VERSION 5.7 ;
  NOWIREEXTENSIONATPIN ON ;
  DIVIDERCHAR "/" ;
  BUSBITCHARS "[]" ;
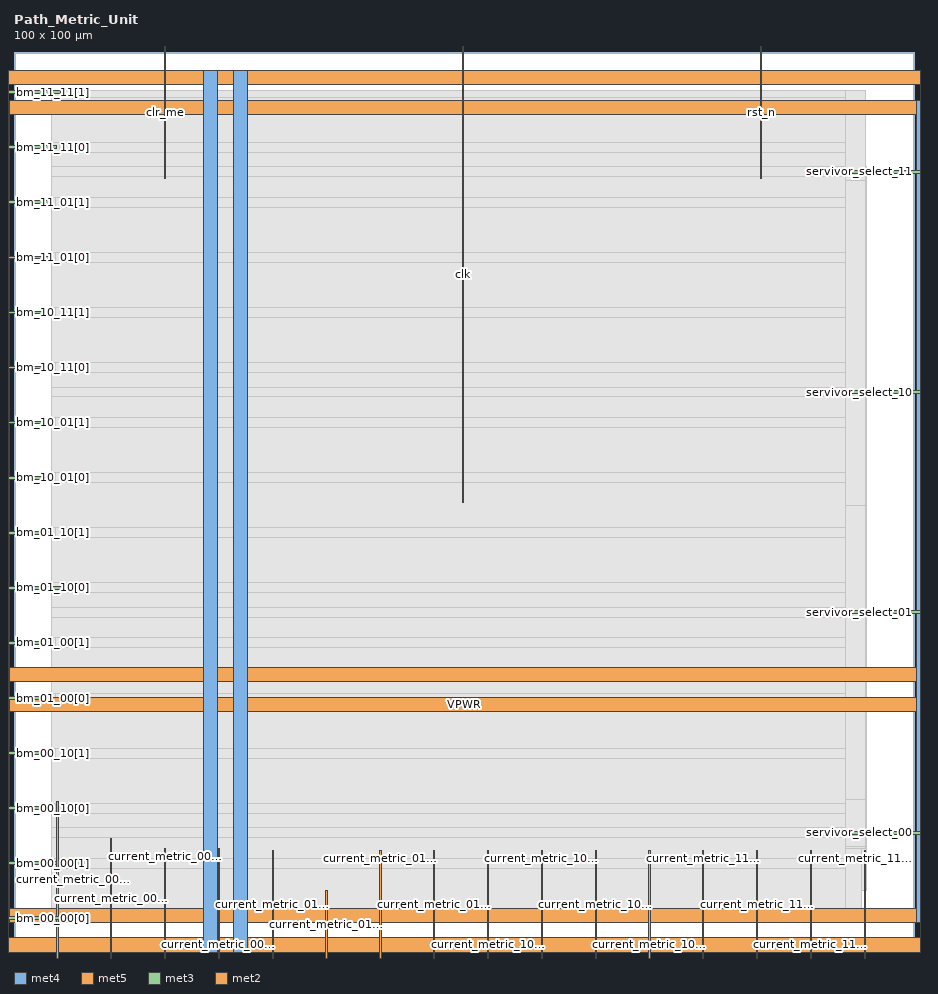
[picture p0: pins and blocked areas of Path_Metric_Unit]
MACRO Path_Metric_Unit
  CLASS BLOCK ;
  FOREIGN Path_Metric_Unit ;
  ORIGIN 0.000 0.000 ;
  SIZE 100.000 BY 100.000 ;
  PIN VGND
    DIRECTION INOUT ;
    USE GROUND ;
    PORT
      LAYER met4 ;
        RECT -5.380 -0.020 -3.780 97.940 ;
    END
    PORT
      LAYER met5 ;
        RECT -5.380 -0.020 105.200 1.580 ;
    END
    PORT
      LAYER met5 ;
        RECT -5.380 96.340 105.200 97.940 ;
    END
    PORT
      LAYER met4 ;
        RECT 103.600 -0.020 105.200 97.940 ;
    END
    PORT
      LAYER met4 ;
        RECT 24.340 -0.020 25.940 97.940 ;
    END
    PORT
      LAYER met5 ;
        RECT -5.380 30.030 105.200 31.630 ;
    END
  END VGND
  PIN VPWR
    DIRECTION INOUT ;
    USE POWER ;
    PORT
      LAYER met4 ;
        RECT -2.080 3.280 -0.480 94.640 ;
    END
    PORT
      LAYER met5 ;
        RECT -2.080 3.280 101.900 4.880 ;
    END
    PORT
      LAYER met5 ;
        RECT -2.080 93.040 101.900 94.640 ;
    END
    PORT
      LAYER met4 ;
        RECT 100.300 3.280 101.900 94.640 ;
    END
    PORT
      LAYER met4 ;
        RECT 21.040 -0.020 22.640 97.940 ;
    END
    PORT
      LAYER met5 ;
        RECT -5.380 26.730 105.200 28.330 ;
    END
  END VPWR
  PIN bm_00_00[0]
    DIRECTION INPUT ;
    USE SIGNAL ;
    ANTENNAGATEAREA 0.196500 ;
    PORT
      LAYER met3 ;
        RECT -1.000 3.590 6.530 3.890 ;
    END
  END bm_00_00[0]
  PIN bm_00_00[1]
    DIRECTION INPUT ;
    USE SIGNAL ;
    ANTENNAGATEAREA 0.196500 ;
    PORT
      LAYER met3 ;
        RECT -1.000 9.710 7.450 10.010 ;
    END
  END bm_00_00[1]
  PIN bm_00_10[0]
    DIRECTION INPUT ;
    USE SIGNAL ;
    ANTENNAGATEAREA 0.196500 ;
    PORT
      LAYER met3 ;
        RECT -1.000 15.830 4.230 16.130 ;
    END
  END bm_00_10[0]
  PIN bm_00_10[1]
    DIRECTION INPUT ;
    USE SIGNAL ;
    ANTENNAGATEAREA 0.196500 ;
    PORT
      LAYER met3 ;
        RECT -1.000 21.950 4.230 22.250 ;
    END
  END bm_00_10[1]
  PIN bm_01_00[0]
    DIRECTION INPUT ;
    USE SIGNAL ;
    ANTENNAGATEAREA 0.196500 ;
    PORT
      LAYER met3 ;
        RECT -1.000 28.070 4.230 28.370 ;
    END
  END bm_01_00[0]
  PIN bm_01_00[1]
    DIRECTION INPUT ;
    USE SIGNAL ;
    ANTENNAGATEAREA 0.196500 ;
    PORT
      LAYER met3 ;
        RECT -1.000 34.190 4.230 34.490 ;
    END
  END bm_01_00[1]
  PIN bm_01_10[0]
    DIRECTION INPUT ;
    USE SIGNAL ;
    ANTENNAGATEAREA 0.196500 ;
    PORT
      LAYER met3 ;
        RECT -1.000 40.310 6.990 40.610 ;
    END
  END bm_01_10[0]
  PIN bm_01_10[1]
    DIRECTION INPUT ;
    USE SIGNAL ;
    ANTENNAGATEAREA 0.196500 ;
    PORT
      LAYER met3 ;
        RECT -1.000 46.430 4.230 46.730 ;
    END
  END bm_01_10[1]
  PIN bm_10_01[0]
    DIRECTION INPUT ;
    USE SIGNAL ;
    ANTENNAGATEAREA 0.196500 ;
    PORT
      LAYER met3 ;
        RECT -1.000 52.550 4.230 52.850 ;
    END
  END bm_10_01[0]
  PIN bm_10_01[1]
    DIRECTION INPUT ;
    USE SIGNAL ;
    ANTENNAGATEAREA 0.196500 ;
    PORT
      LAYER met3 ;
        RECT -1.000 58.670 4.230 58.970 ;
    END
  END bm_10_01[1]
  PIN bm_10_11[0]
    DIRECTION INPUT ;
    USE SIGNAL ;
    ANTENNAGATEAREA 0.196500 ;
    PORT
      LAYER met3 ;
        RECT -1.000 64.790 4.230 65.090 ;
    END
  END bm_10_11[0]
  PIN bm_10_11[1]
    DIRECTION INPUT ;
    USE SIGNAL ;
    ANTENNAGATEAREA 0.196500 ;
    PORT
      LAYER met3 ;
        RECT -1.000 70.910 4.230 71.210 ;
    END
  END bm_10_11[1]
  PIN bm_11_01[0]
    DIRECTION INPUT ;
    USE SIGNAL ;
    ANTENNAGATEAREA 0.196500 ;
    PORT
      LAYER met3 ;
        RECT -1.000 77.030 4.230 77.330 ;
    END
  END bm_11_01[0]
  PIN bm_11_01[1]
    DIRECTION INPUT ;
    USE SIGNAL ;
    ANTENNAGATEAREA 0.196500 ;
    PORT
      LAYER met3 ;
        RECT -1.000 83.150 4.230 83.450 ;
    END
  END bm_11_01[1]
  PIN bm_11_11[0]
    DIRECTION INPUT ;
    USE SIGNAL ;
    ANTENNAGATEAREA 0.196500 ;
    PORT
      LAYER met3 ;
        RECT -1.000 89.270 4.690 89.570 ;
    END
  END bm_11_11[0]
  PIN bm_11_11[1]
    DIRECTION INPUT ;
    USE SIGNAL ;
    ANTENNAGATEAREA 0.196500 ;
    PORT
      LAYER met3 ;
        RECT -1.000 95.390 5.150 95.690 ;
    END
  END bm_11_11[1]
  PIN clk
    DIRECTION INPUT ;
    USE SIGNAL ;
    ANTENNAGATEAREA 0.852000 ;
    PORT
      LAYER met2 ;
        RECT 49.840 49.940 49.980 101.000 ;
    END
  END clk
  PIN clr_me
    DIRECTION INPUT ;
    USE SIGNAL ;
    ANTENNAGATEAREA 0.196500 ;
    PORT
      LAYER met2 ;
        RECT 16.720 85.980 16.860 101.000 ;
    END
  END clr_me
  PIN current_metric_00[0]
    DIRECTION OUTPUT ;
    USE SIGNAL ;
    ANTENNADIFFAREA 0.445500 ;
    PORT
      LAYER met2 ;
        RECT 4.760 -1.000 4.900 16.700 ;
    END
  END current_metric_00[0]
  PIN current_metric_00[1]
    DIRECTION OUTPUT ;
    USE SIGNAL ;
    ANTENNADIFFAREA 0.445500 ;
    PORT
      LAYER met2 ;
        RECT 10.740 -1.000 10.880 12.620 ;
    END
  END current_metric_00[1]
  PIN current_metric_00[2]
    DIRECTION OUTPUT ;
    USE SIGNAL ;
    ANTENNADIFFAREA 0.445500 ;
    PORT
      LAYER met2 ;
        RECT 16.720 -1.000 16.860 11.460 ;
    END
  END current_metric_00[2]
  PIN current_metric_00[3]
    DIRECTION OUTPUT ;
    USE SIGNAL ;
    ANTENNADIFFAREA 0.445500 ;
    PORT
      LAYER met2 ;
        RECT 22.700 -1.000 22.840 11.460 ;
    END
  END current_metric_00[3]
  PIN current_metric_01[0]
    DIRECTION OUTPUT ;
    USE SIGNAL ;
    ANTENNADIFFAREA 0.445500 ;
    PORT
      LAYER met2 ;
        RECT 28.680 -1.000 28.820 11.260 ;
    END
  END current_metric_01[0]
  PIN current_metric_01[1]
    DIRECTION OUTPUT ;
    USE SIGNAL ;
    ANTENNADIFFAREA 0.445500 ;
    PORT
      LAYER met2 ;
        RECT 34.660 -1.000 34.800 6.840 ;
    END
  END current_metric_01[1]
  PIN current_metric_01[2]
    DIRECTION OUTPUT ;
    USE SIGNAL ;
    ANTENNADIFFAREA 0.445500 ;
    PORT
      LAYER met2 ;
        RECT 40.640 -1.000 40.780 11.260 ;
    END
  END current_metric_01[2]
  PIN current_metric_01[3]
    DIRECTION OUTPUT ;
    USE SIGNAL ;
    ANTENNADIFFAREA 0.445500 ;
    PORT
      LAYER met2 ;
        RECT 46.620 -1.000 46.760 11.260 ;
    END
  END current_metric_01[3]
  PIN current_metric_10[0]
    DIRECTION OUTPUT ;
    USE SIGNAL ;
    ANTENNADIFFAREA 0.445500 ;
    PORT
      LAYER met2 ;
        RECT 52.600 -1.000 52.740 11.260 ;
    END
  END current_metric_10[0]
  PIN current_metric_10[1]
    DIRECTION OUTPUT ;
    USE SIGNAL ;
    ANTENNADIFFAREA 0.445500 ;
    PORT
      LAYER met2 ;
        RECT 58.580 -1.000 58.720 11.260 ;
    END
  END current_metric_10[1]
  PIN current_metric_10[2]
    DIRECTION OUTPUT ;
    USE SIGNAL ;
    ANTENNADIFFAREA 0.445500 ;
    PORT
      LAYER met2 ;
        RECT 64.560 -1.000 64.700 11.260 ;
    END
  END current_metric_10[2]
  PIN current_metric_10[3]
    DIRECTION OUTPUT ;
    USE SIGNAL ;
    ANTENNADIFFAREA 0.445500 ;
    PORT
      LAYER met2 ;
        RECT 70.540 -1.000 70.680 11.260 ;
    END
  END current_metric_10[3]
  PIN current_metric_11[0]
    DIRECTION OUTPUT ;
    USE SIGNAL ;
    ANTENNADIFFAREA 0.445500 ;
    PORT
      LAYER met2 ;
        RECT 76.520 -1.000 76.660 11.260 ;
    END
  END current_metric_11[0]
  PIN current_metric_11[1]
    DIRECTION OUTPUT ;
    USE SIGNAL ;
    ANTENNADIFFAREA 0.445500 ;
    PORT
      LAYER met2 ;
        RECT 82.500 -1.000 82.640 11.260 ;
    END
  END current_metric_11[1]
  PIN current_metric_11[2]
    DIRECTION OUTPUT ;
    USE SIGNAL ;
    ANTENNADIFFAREA 0.445500 ;
    PORT
      LAYER met2 ;
        RECT 88.480 -1.000 88.620 11.260 ;
    END
  END current_metric_11[2]
  PIN current_metric_11[3]
    DIRECTION OUTPUT ;
    USE SIGNAL ;
    ANTENNADIFFAREA 0.445500 ;
    PORT
      LAYER met2 ;
        RECT 94.460 -1.000 94.600 11.260 ;
    END
  END current_metric_11[3]
  PIN rst_n
    DIRECTION INPUT ;
    USE SIGNAL ;
    ANTENNAGATEAREA 0.196500 ;
    PORT
      LAYER met2 ;
        RECT 82.960 85.980 83.100 101.000 ;
    END
  END rst_n
  PIN servivor_select_00
    DIRECTION OUTPUT ;
    USE SIGNAL ;
    ANTENNADIFFAREA 0.445500 ;
    PORT
      LAYER met3 ;
        RECT 92.370 13.110 101.000 13.410 ;
    END
  END servivor_select_00
  PIN servivor_select_01
    DIRECTION OUTPUT ;
    USE SIGNAL ;
    ANTENNADIFFAREA 0.445500 ;
    PORT
      LAYER met3 ;
        RECT 92.370 37.590 101.000 37.890 ;
    END
  END servivor_select_01
  PIN servivor_select_10
    DIRECTION OUTPUT ;
    USE SIGNAL ;
    ANTENNADIFFAREA 0.445500 ;
    PORT
      LAYER met3 ;
        RECT 92.370 62.070 101.000 62.370 ;
    END
  END servivor_select_10
  PIN servivor_select_11
    DIRECTION OUTPUT ;
    USE SIGNAL ;
    ANTENNADIFFAREA 0.445500 ;
    PORT
      LAYER met3 ;
        RECT 92.370 86.550 101.000 86.850 ;
    END
  END servivor_select_11
  OBS
      LAYER nwell ;
        RECT 5.330 10.795 94.490 87.125 ;
      LAYER li1 ;
        RECT 5.520 10.795 94.300 87.125 ;
      LAYER met1 ;
        RECT 4.210 6.840 94.690 87.280 ;
      LAYER met2 ;
        RECT 4.230 85.700 16.440 95.725 ;
        RECT 17.140 85.700 49.560 95.725 ;
        RECT 4.230 49.660 49.560 85.700 ;
        RECT 50.260 85.700 82.680 95.725 ;
        RECT 83.380 85.700 94.660 95.725 ;
        RECT 50.260 49.660 94.660 85.700 ;
        RECT 4.230 16.980 94.660 49.660 ;
        RECT 4.230 3.555 4.480 16.980 ;
        RECT 5.180 12.900 94.660 16.980 ;
        RECT 5.180 3.555 10.460 12.900 ;
        RECT 11.160 11.740 94.660 12.900 ;
        RECT 11.160 3.555 16.440 11.740 ;
        RECT 17.140 3.555 22.420 11.740 ;
        RECT 23.120 11.540 94.660 11.740 ;
        RECT 23.120 3.555 28.400 11.540 ;
        RECT 29.100 7.120 40.360 11.540 ;
        RECT 29.100 3.555 34.380 7.120 ;
        RECT 35.080 3.555 40.360 7.120 ;
        RECT 41.060 3.555 46.340 11.540 ;
        RECT 47.040 3.555 52.320 11.540 ;
        RECT 53.020 3.555 58.300 11.540 ;
        RECT 59.000 3.555 64.280 11.540 ;
        RECT 64.980 3.555 70.260 11.540 ;
        RECT 70.960 3.555 76.240 11.540 ;
        RECT 76.940 3.555 82.220 11.540 ;
        RECT 82.920 3.555 88.200 11.540 ;
        RECT 88.900 3.555 94.180 11.540 ;
      LAYER met3 ;
        RECT 5.550 94.990 92.395 95.705 ;
        RECT 4.205 89.970 92.395 94.990 ;
        RECT 5.090 88.870 92.395 89.970 ;
        RECT 4.205 87.250 92.395 88.870 ;
        RECT 4.205 86.150 91.970 87.250 ;
        RECT 4.205 83.850 92.395 86.150 ;
        RECT 4.630 82.750 92.395 83.850 ;
        RECT 4.205 77.730 92.395 82.750 ;
        RECT 4.630 76.630 92.395 77.730 ;
        RECT 4.205 71.610 92.395 76.630 ;
        RECT 4.630 70.510 92.395 71.610 ;
        RECT 4.205 65.490 92.395 70.510 ;
        RECT 4.630 64.390 92.395 65.490 ;
        RECT 4.205 62.770 92.395 64.390 ;
        RECT 4.205 61.670 91.970 62.770 ;
        RECT 4.205 59.370 92.395 61.670 ;
        RECT 4.630 58.270 92.395 59.370 ;
        RECT 4.205 53.250 92.395 58.270 ;
        RECT 4.630 52.150 92.395 53.250 ;
        RECT 4.205 47.130 92.395 52.150 ;
        RECT 4.630 46.030 92.395 47.130 ;
        RECT 4.205 41.010 92.395 46.030 ;
        RECT 7.390 39.910 92.395 41.010 ;
        RECT 4.205 38.290 92.395 39.910 ;
        RECT 4.205 37.190 91.970 38.290 ;
        RECT 4.205 34.890 92.395 37.190 ;
        RECT 4.630 33.790 92.395 34.890 ;
        RECT 4.205 28.770 92.395 33.790 ;
        RECT 4.630 27.670 92.395 28.770 ;
        RECT 4.205 22.650 92.395 27.670 ;
        RECT 4.630 21.550 92.395 22.650 ;
        RECT 4.205 16.530 92.395 21.550 ;
        RECT 4.630 15.430 92.395 16.530 ;
        RECT 4.205 13.810 92.395 15.430 ;
        RECT 4.205 12.710 91.970 13.810 ;
        RECT 4.205 10.410 92.395 12.710 ;
        RECT 7.850 9.310 92.395 10.410 ;
        RECT 4.205 4.290 92.395 9.310 ;
        RECT 6.930 3.575 92.395 4.290 ;
  END
END Path_Metric_Unit
END LIBRARY

